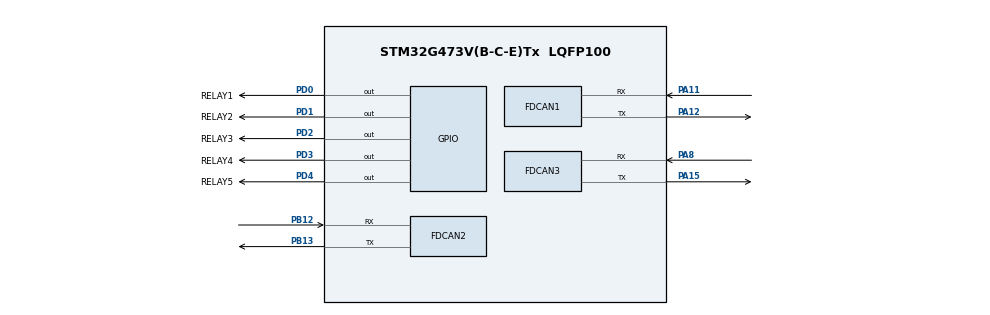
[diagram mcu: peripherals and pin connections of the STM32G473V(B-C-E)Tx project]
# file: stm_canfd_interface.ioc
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FDCAN1.AutoRetransmission=ENABLE
FDCAN1.DataPrescaler=2
FDCAN1.DataSyncJumpWidth=4
FDCAN1.DataTimeSeg1=15
FDCAN1.DataTimeSeg2=4
FDCAN1.FrameFormat=FDCAN_FRAME_FD_BRS
FDCAN1.NominalPrescaler=8
FDCAN1.NominalSyncJumpWidth=4
FDCAN1.NominalTimeSeg1=14
FDCAN1.NominalTimeSeg2=5
FDCAN2.AutoRetransmission=ENABLE
FDCAN2.DataPrescaler=2
FDCAN2.DataSyncJumpWidth=4
FDCAN2.DataTimeSeg1=15
FDCAN2.DataTimeSeg2=4
FDCAN2.FrameFormat=FDCAN_FRAME_FD_BRS
FDCAN2.NominalPrescaler=8
FDCAN2.NominalSyncJumpWidth=4
FDCAN2.NominalTimeSeg1=14
FDCAN2.NominalTimeSeg2=5
FDCAN3.AutoRetransmission=ENABLE
FDCAN3.DataPrescaler=2
FDCAN3.DataSyncJumpWidth=4
FDCAN3.DataTimeSeg1=15
FDCAN3.DataTimeSeg2=4
FDCAN3.FrameFormat=FDCAN_FRAME_FD_BRS
FDCAN3.NominalPrescaler=8
FDCAN3.NominalSyncJumpWidth=4
FDCAN3.NominalTimeSeg1=14
FDCAN3.NominalTimeSeg2=5
FREERTOS.INCLUDE_eTaskGetState=1
FREERTOS.INCLUDE_uxTaskGetStackHighWaterMark=1
FREERTOS.INCLUDE_vTaskDelayUntil=1
FREERTOS.INCLUDE_xTaskGetCurrentTaskHandle=1
FREERTOS.MEMORY_ALLOCATION=2
FREERTOS.Tasks01=defaultTask,0,256,StartDefaultTask,Default,NULL,Dynamic,NULL,NULL
FREERTOS.Timers01=task_5ms,task_5ms_callback,osTimerPeriodic,Default,NULL,Static,task_5msControlBlock;task_10ms,task_10ms_callback,osTimerPeriodic,Default,NULL,Static,task_10msControlBlock;task_100ms,task_100ms_callback,osTimerPeriodic,Default,NULL,Static,task_100msControlBlock
FREERTOS.configCHECK_FOR_STACK_OVERFLOW=1
FREERTOS.configMINIMAL_STACK_SIZE=256
FREERTOS.configRECORD_STACK_HIGH_ADDRESS=1
FREERTOS.configTIMER_TASK_PRIORITY=3
FREERTOS.configTOTAL_HEAP_SIZE=15360
FREERTOS.configUSE_TIMERS=1
Mcu.Family=STM32G4
Mcu.Name=STM32G473V(B-C-E)Tx
Mcu.Package=LQFP100
NVIC.FDCAN1_IT0_IRQn=true\:5\:0\:false\:false\:true\:true\:true\:true\:true
NVIC.FDCAN2_IT0_IRQn=true\:5\:0\:false\:false\:true\:true\:true\:true\:true
NVIC.FDCAN3_IT0_IRQn=true\:5\:0\:false\:false\:true\:true\:true\:true\:true
NVIC.PriorityGroup=NVIC_PRIORITYGROUP_4
NVIC.TIM3_IRQn=true\:5\:0\:false\:false\:true\:true\:true\:true\:true
NVIC.TIM6_DAC_IRQn=true\:5\:0\:false\:false\:true\:true\:true\:true\:true
NVIC.TIM7_DAC_IRQn=true\:0\:0\:false\:false\:true\:false\:false\:true\:true
NVIC.TimeBase=TIM7_DAC_IRQn
NVIC.TimeBaseIP=TIM7
PA11.Mode=FDCAN_Activate
PA11.Signal=FDCAN1_RX
PA12.Mode=FDCAN_Activate
PA12.Signal=FDCAN1_TX
PA13.Mode=Trace_Asynchronous_SW
PA13.Signal=SYS_JTMS-SWDIO
PA14.Mode=Trace_Asynchronous_SW
PA14.Signal=SYS_JTCK-SWCLK
PA15.Mode=FDCAN_Activate
PA15.Signal=FDCAN3_TX
PA8.Mode=FDCAN_Activate
PA8.Signal=FDCAN3_RX
PB12.Mode=FDCAN_Activate
PB12.Signal=FDCAN2_RX
PB13.Mode=FDCAN_Activate
PB13.Signal=FDCAN2_TX
PB3.Mode=Trace_Asynchronous_SW
PB3.Signal=SYS_JTDO-SWO
PD0.GPIO_Label=RELAY1
PD0.Signal=GPIO_Output
PD1.GPIO_Label=RELAY2
PD1.Signal=GPIO_Output
PD2.GPIO_Label=RELAY3
PD2.Signal=GPIO_Output
PD3.GPIO_Label=RELAY4
PD3.Signal=GPIO_Output
PD4.GPIO_Label=RELAY5
PD4.Signal=GPIO_Output
PF0-OSC_IN.Mode=HSE-External-Oscillator
PF0-OSC_IN.Signal=RCC_OSC_IN
PF1-OSC_OUT.Mode=HSE-External-Oscillator
PF1-OSC_OUT.Signal=RCC_OSC_OUT
ProjectManager.HeapSize=0x200
ProjectManager.StackSize=0x400
ProjectManager.TargetToolchain=STM32CubeIDE
RCC.ADC12Freq_Value=80000000
RCC.ADC345Freq_Value=80000000
RCC.AHBFreq_Value=80000000
RCC.APB1Freq_Value=80000000
RCC.APB1TimFreq_Value=80000000
RCC.APB2Freq_Value=80000000
RCC.APB2TimFreq_Value=80000000
RCC.CortexFreq_Value=80000000
RCC.EXTERNAL_CLOCK_VALUE=12288000
RCC.FDCANCLockSelection=RCC_FDCANCLKSOURCE_PLL
RCC.HCLKFreq_Value=80000000
RCC.HSE_VALUE=8000000
RCC.HSI48_VALUE=48000000
RCC.HSI_VALUE=16000000
RCC.LSE_VALUE=32768
RCC.PLLN=20
RCC.PLLSourceVirtual=RCC_PLLSOURCE_HSE
RCC.SYSCLKFreq_VALUE=80000000
RCC.SYSCLKSource=RCC_SYSCLKSOURCE_PLLCLK
RCC.USBFreq_Value=80000000
RCC.VCOOutputFreq_Value=160000000
TIM3.Prescaler=199
TIM3.TIM_MasterOutputTrigger=TIM_TRGO_UPDATE
TIM6.PeriodNoDither=999
TIM6.Prescaler=799
VP_FREERTOS_VS_CMSIS_V1.Mode=CMSIS_V1
VP_SYS_VS_DBSignals.Mode=DisableDeadBatterySignals
VP_SYS_VS_tim7.Mode=TIM7
VP_TIM3_VS_ClockSourceINT.Mode=Internal
VP_TIM6_VS_ClockSourceINT.Mode=Enable_Timer
board=custom

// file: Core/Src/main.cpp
/* USER CODE BEGIN Header */
/**
 ******************************************************************************
 * @file           : main.c
 * @brief          : Main program body
 ******************************************************************************
 * @attention
 *
 * <h2><center>&copy; Copyright (c) 2021 STMicroelectronics.
 * All rights reserved.</center></h2>
 *
 * This software component is licensed by ST under BSD 3-Clause license,
 * the "License"; You may not use this file except in compliance with the
 * License. You may obtain a copy of the License at:
 *                        opensource.org/licenses/BSD-3-Clause
 *
 ******************************************************************************
 */
/* USER CODE END Header */
#include "main.h"
#include "cmsis_os.h"
/* USER CODE BEGIN Includes */
//* bsw
#include "bsw/interface/can_transfer.hpp"
#include "bsw/interface/io_function.hpp"
#include "bsw/interface/adc.hpp"
#include "bsw/interface/dac.hpp"
#include "bsw/buffer.hpp"

//* rte
#include "rte.hpp"
//#include "can_transfer.h"
/* USER CODE END Includes */

ADC_HandleTypeDef hadc1;
DMA_HandleTypeDef hdma_adc1;

DAC_HandleTypeDef hdac1;
DAC_HandleTypeDef hdac2;
DAC_HandleTypeDef hdac3;

OPAMP_HandleTypeDef hopamp1;

FDCAN_HandleTypeDef hfdcan1;
FDCAN_HandleTypeDef hfdcan2;
FDCAN_HandleTypeDef hfdcan3;

TIM_HandleTypeDef htim3;
TIM_HandleTypeDef htim6;

osThreadId defaultTaskHandle;

osTimerId task_10msHandle;
osStaticTimerDef_t task_10msControlBlock;
osTimerId task_20msHandle;
osStaticTimerDef_t task_20msControlBlock;
osTimerId task_40msHandle;
osStaticTimerDef_t task_40msControlBlock;
osTimerId task_50msHandle;
osStaticTimerDef_t task_50msControlBlock;
osTimerId task_100msHandle;
osStaticTimerDef_t task_100msControlBlock;
osTimerId task_200msHandle;
osStaticTimerDef_t task_200msControlBlock;
/* USER CODE BEGIN PV */
// bsw handle
bsw::interface::CanTransfer can_transfer_;
bsw::interface::IoFunction io_function_;
bsw::interface::Buffer user_buffer_;

// rte handler
//* ADC_DAC_ENABLE
bsw::interface::AdcReader adc_reader_;
bsw::interface::DacWriter dac_writer_;
rte::Rte rte_(&can_transfer_, &io_function_);

/* USER CODE END PV */

void SystemClock_Config(void);
static void MX_GPIO_Init(void);

static void MX_FDCAN1_Init(void);
static void MX_FDCAN2_Init(void);
static void MX_FDCAN3_Init(void);

static void MX_TIM3_Init(void);
static void MX_TIM6_Init(void);

static void MX_DMA_Init(void);
static void MX_ADC1_Init(void);
static void MX_ADC1_Init(void);
static void MX_DAC1_Init(void);
static void MX_DAC2_Init(void);
static void MX_DAC3_Init(void);
static void MX_OPAMP1_Init(void);

void StartDefaultTask(void const * argument);
void task_10ms_callback(void const * argument);
void task_20ms_callback(void const * argument);
void task_40ms_callback(void const * argument);
void task_50ms_callback(void const * argument);
void task_100ms_callback(void const * argument);
void task_200ms_callback(void const * argument);

/* USER CODE BEGIN 0 */
#ifdef DEBUG
	static void VectorBase_Config(void)
	{
	  /* The constant array with vectors of the vector table is declared externally in the
	   * c-startup code.
	   */
	  extern const unsigned long g_pfnVectors[];

	  /* Remap the vector table to where the vector table is located for this program. */
	  SCB->VTOR = (unsigned long)&g_pfnVectors[0];
	}

	extern "C" {
		int _write(int file, char *ptr, int len)
		{
			for (int DataIdx = 0; DataIdx < len; DataIdx++)
				ITM_SendChar(*ptr++);

			return len;
		}
	}
#endif

/* USER CODE END 0 */

int main(void)
{
	//* initialize user defined buffer (for A1 interface)
	can_transfer_.initUserBuffer(&user_buffer_);
	can_transfer_.setBus2DeviceBypassMode(false);
	can_transfer_.setMsgFilteringMode(false);

  /* USER CODE BEGIN 1 */
#ifdef DEBUG
  VectorBase_Config();
#endif
  /* USER CODE END 1 */

  /* MCU Configuration--------------------------------------------------------*/

  /* Reset of all peripherals, Initializes the Flash interface and the Systick. */
  HAL_Init();

  /* Configure the system clock */
  SystemClock_Config();

  /* Initialize all configured peripherals */
  MX_GPIO_Init();

  MX_FDCAN1_Init();
  MX_FDCAN2_Init();
  MX_FDCAN3_Init();

  MX_TIM6_Init();
  MX_TIM3_Init();

  //* ADC_DAC_ENABLE
//  MX_DMA_Init();
//  MX_ADC1_Init();
//  MX_DAC1_Init();
//  MX_DAC2_Init();
//  MX_DAC3_Init();
  MX_OPAMP1_Init();

  /* Create the timer(s) */
  /* definition and creation of task_20ms */
  osTimerStaticDef(task_20ms, task_20ms_callback, &task_20msControlBlock);
  task_20msHandle = osTimerCreate(osTimer(task_20ms), osTimerPeriodic, NULL);
  /* definition and creation of task_100ms */
  osTimerStaticDef(task_100ms, task_100ms_callback, &task_100msControlBlock);
  task_100msHandle = osTimerCreate(osTimer(task_100ms), osTimerPeriodic, NULL);
  /* definition and creation of task_200ms */
  osTimerStaticDef(task_200ms, task_200ms_callback, &task_200msControlBlock);
  task_200msHandle = osTimerCreate(osTimer(task_200ms), osTimerPeriodic, NULL);

  /* USER CODE BEGIN RTOS_TIMERS */
  osTimerStart(task_20msHandle, 20);
  osTimerStart(task_100msHandle, 100);
  osTimerStart(task_200msHandle, 200);

  /* start timers, add new ones, ... */
  /* USER CODE END RTOS_TIMERS */

  /* Create the thread(s) */
  /* definition and creation of defaultTask */
  std::string task_name = "defaultTask";
  const osThreadDef_t os_thread_def_defaultTask = {(char*)task_name.c_str(),
												  StartDefaultTask,
												  osPriorityIdle,
												  0,
												  256,
												  NULL,
												  NULL};
  defaultTaskHandle = osThreadCreate(osThread(defaultTask), NULL);

  /* USER CODE BEGIN RTOS_THREADS */
	/* add threads, ... */
  // RTE initialize

  /* USER CODE END RTOS_THREADS */

  /* Start scheduler */
  osKernelStart();

  /* We should never get here as control is now taken by the scheduler */
  /* Infinite loop */
	while (1)
	{

	}
}

void SystemClock_Config(void)
{
  RCC_OscInitTypeDef RCC_OscInitStruct = {0};
  RCC_ClkInitTypeDef RCC_ClkInitStruct = {0};
  RCC_PeriphCLKInitTypeDef PeriphClkInit = {0};

  /** Configure the main internal regulator output voltage
  */
  HAL_PWREx_ControlVoltageScaling(PWR_REGULATOR_VOLTAGE_SCALE1_BOOST);
  /** Initializes the RCC Oscillators according to the specified parameters
  * in the RCC_OscInitTypeDef structure.
  */
  RCC_OscInitStruct.OscillatorType = RCC_OSCILLATORTYPE_HSE;
  RCC_OscInitStruct.HSEState = RCC_HSE_ON;
  RCC_OscInitStruct.PLL.PLLState = RCC_PLL_ON;
  RCC_OscInitStruct.PLL.PLLSource = RCC_PLLSOURCE_HSE;
  RCC_OscInitStruct.PLL.PLLM = RCC_PLLM_DIV1;
  RCC_OscInitStruct.PLL.PLLN = 40;
  RCC_OscInitStruct.PLL.PLLP = RCC_PLLP_DIV2;
  RCC_OscInitStruct.PLL.PLLQ = RCC_PLLQ_DIV4;
  RCC_OscInitStruct.PLL.PLLR = RCC_PLLR_DIV2;
  if (HAL_RCC_OscConfig(&RCC_OscInitStruct) != HAL_OK)
  {
    Error_Handler();
  }
  /** Initializes the CPU, AHB and APB buses clocks
  */
  RCC_ClkInitStruct.ClockType = RCC_CLOCKTYPE_HCLK|RCC_CLOCKTYPE_SYSCLK
                              |RCC_CLOCKTYPE_PCLK1|RCC_CLOCKTYPE_PCLK2;
  RCC_ClkInitStruct.SYSCLKSource = RCC_SYSCLKSOURCE_PLLCLK;
  RCC_ClkInitStruct.AHBCLKDivider = RCC_SYSCLK_DIV1;
  RCC_ClkInitStruct.APB1CLKDivider = RCC_HCLK_DIV1;
  RCC_ClkInitStruct.APB2CLKDivider = RCC_HCLK_DIV1;

  if (HAL_RCC_ClockConfig(&RCC_ClkInitStruct, FLASH_LATENCY_4) != HAL_OK)
  {
    Error_Handler();
  }
  /** Initializes the peripherals clocks
  */
  PeriphClkInit.PeriphClockSelection = RCC_PERIPHCLK_FDCAN;
  PeriphClkInit.FdcanClockSelection = RCC_FDCANCLKSOURCE_PLL;
  if (HAL_RCCEx_PeriphCLKConfig(&PeriphClkInit) != HAL_OK)
  {
    Error_Handler();
  }
}

static void MX_FDCAN1_Init(void)
{

  hfdcan1.Instance = FDCAN1;
  hfdcan1.Init.ClockDivider = FDCAN_CLOCK_DIV1;
  hfdcan1.Init.FrameFormat = FDCAN_FRAME_FD_BRS;
  hfdcan1.Init.Mode = FDCAN_MODE_NORMAL;
  hfdcan1.Init.AutoRetransmission = ENABLE;
  hfdcan1.Init.TransmitPause = DISABLE;
  hfdcan1.Init.ProtocolException = DISABLE;
  hfdcan1.Init.NominalPrescaler = 16;
  hfdcan1.Init.NominalSyncJumpWidth = 2;
  hfdcan1.Init.NominalTimeSeg1 = 7;
  hfdcan1.Init.NominalTimeSeg2 = 2;
  hfdcan1.Init.DataPrescaler = 2;
  hfdcan1.Init.DataSyncJumpWidth = 4;
  hfdcan1.Init.DataTimeSeg1 = 15;
  hfdcan1.Init.DataTimeSeg2 = 4;
  uint8_t buffer_size = can_transfer_.getBufferSize(CAN_CH1);
  hfdcan1.Init.StdFiltersNbr = buffer_size/2 + buffer_size%2;
  hfdcan1.Init.ExtFiltersNbr = 0;
  hfdcan1.Init.TxFifoQueueMode = FDCAN_TX_FIFO_OPERATION;

}

static void MX_FDCAN2_Init(void)
{

  hfdcan2.Instance = FDCAN2;
  hfdcan2.Init.FrameFormat = FDCAN_FRAME_FD_BRS;
  hfdcan2.Init.Mode = FDCAN_MODE_NORMAL;
  hfdcan2.Init.AutoRetransmission = ENABLE;
  hfdcan2.Init.TransmitPause = DISABLE;
  hfdcan2.Init.ProtocolException = DISABLE;
  hfdcan2.Init.NominalPrescaler = 16;
  hfdcan2.Init.NominalSyncJumpWidth = 2;
  hfdcan2.Init.NominalTimeSeg1 = 7;
  hfdcan2.Init.NominalTimeSeg2 = 2;
  hfdcan2.Init.DataPrescaler = 2;
  hfdcan2.Init.DataSyncJumpWidth = 4;
  hfdcan2.Init.DataTimeSeg1 = 15;
  hfdcan2.Init.DataTimeSeg2 = 4;
  uint8_t buffer_size = can_transfer_.getBufferSize(CAN_CH2);
  hfdcan2.Init.StdFiltersNbr = buffer_size/2 + buffer_size%2;
  hfdcan2.Init.ExtFiltersNbr = 0;
  hfdcan2.Init.TxFifoQueueMode = FDCAN_TX_FIFO_OPERATION;

}

static void MX_FDCAN3_Init(void)
{

  hfdcan3.Instance = FDCAN3;
  hfdcan3.Init.FrameFormat = FDCAN_FRAME_FD_BRS;
  hfdcan3.Init.Mode = FDCAN_MODE_NORMAL;
  hfdcan3.Init.AutoRetransmission = ENABLE;
  hfdcan3.Init.TransmitPause = DISABLE;
  hfdcan3.Init.ProtocolException = DISABLE;
  hfdcan3.Init.NominalPrescaler = 16;
  hfdcan3.Init.NominalSyncJumpWidth = 2;
  hfdcan3.Init.NominalTimeSeg1 = 7;
  hfdcan3.Init.NominalTimeSeg2 = 2;
  hfdcan3.Init.DataPrescaler = 2;
  hfdcan3.Init.DataSyncJumpWidth = 4;
  hfdcan3.Init.DataTimeSeg1 = 15;
  hfdcan3.Init.DataTimeSeg2 = 4;
  uint8_t buffer_size = can_transfer_.getBufferSize(CAN_CH3);
  hfdcan3.Init.StdFiltersNbr = buffer_size/2 + buffer_size%2;
  hfdcan3.Init.ExtFiltersNbr = 0;
  hfdcan3.Init.TxFifoQueueMode = FDCAN_TX_FIFO_OPERATION;

}

static void MX_TIM3_Init(void)
{

  TIM_ClockConfigTypeDef sClockSourceConfig = {0};
  TIM_MasterConfigTypeDef sMasterConfig = {0};

  htim3.Instance = TIM3;
  htim3.Init.Prescaler = 199;
  htim3.Init.CounterMode = TIM_COUNTERMODE_UP;
  htim3.Init.Period = 65535;
  htim3.Init.ClockDivision = TIM_CLOCKDIVISION_DIV1;
  htim3.Init.AutoReloadPreload = TIM_AUTORELOAD_PRELOAD_DISABLE;
  if (HAL_TIM_Base_Init(&htim3) != HAL_OK)
  {
    Error_Handler();
  }
  sClockSourceConfig.ClockSource = TIM_CLOCKSOURCE_INTERNAL;
  if (HAL_TIM_ConfigClockSource(&htim3, &sClockSourceConfig) != HAL_OK)
  {
    Error_Handler();
  }
  sMasterConfig.MasterOutputTrigger = TIM_TRGO_UPDATE;
  sMasterConfig.MasterSlaveMode = TIM_MASTERSLAVEMODE_DISABLE;
  if (HAL_TIMEx_MasterConfigSynchronization(&htim3, &sMasterConfig) != HAL_OK)
  {
    Error_Handler();
  }

}

static void MX_TIM6_Init(void)
{

  TIM_MasterConfigTypeDef sMasterConfig = {0};

  htim6.Instance = TIM6;
  htim6.Init.Prescaler = 799;
  htim6.Init.CounterMode = TIM_COUNTERMODE_UP;
  htim6.Init.Period = 999;
  htim6.Init.AutoReloadPreload = TIM_AUTORELOAD_PRELOAD_DISABLE;
  if (HAL_TIM_Base_Init(&htim6) != HAL_OK)
  {
    Error_Handler();
  }
  sMasterConfig.MasterOutputTrigger = TIM_TRGO_RESET;
  sMasterConfig.MasterSlaveMode = TIM_MASTERSLAVEMODE_DISABLE;
  if (HAL_TIMEx_MasterConfigSynchronization(&htim6, &sMasterConfig) != HAL_OK)
  {
    Error_Handler();
  }

}

static void MX_GPIO_Init(void)
{
  GPIO_InitTypeDef GPIO_InitStruct = {0};

  /* GPIO Ports Clock Enable */
  __HAL_RCC_GPIOF_CLK_ENABLE();
  __HAL_RCC_GPIOC_CLK_ENABLE();
  __HAL_RCC_GPIOB_CLK_ENABLE();
  __HAL_RCC_GPIOA_CLK_ENABLE();
  __HAL_RCC_GPIOD_CLK_ENABLE();
  __HAL_RCC_GPIOE_CLK_ENABLE();

  /*Configure GPIO pin Output Level */
  HAL_GPIO_WritePin(GPIOD, RELAY1_Pin|RELAY2_Pin|RELAY3_Pin|RELAY4_Pin
						  |RELAY5_Pin, GPIO_PIN_RESET);
  HAL_GPIO_WritePin(GPIOE, GPIO_PIN_All, GPIO_PIN_RESET);
  HAL_GPIO_WritePin(GPIOC, GPIO_PIN_1, GPIO_PIN_RESET);

  /*Configure GPIO pins : RELAY1_Pin RELAY2_Pin RELAY3_Pin RELAY4_Pin
						   RELAY5_Pin */
  GPIO_InitStruct.Pin = RELAY1_Pin|RELAY2_Pin|RELAY3_Pin|RELAY4_Pin
						  |RELAY5_Pin;
  GPIO_InitStruct.Mode = GPIO_MODE_OUTPUT_PP;
  GPIO_InitStruct.Pull = GPIO_NOPULL;
  GPIO_InitStruct.Speed = GPIO_SPEED_FREQ_LOW;
  HAL_GPIO_Init(GPIOD, &GPIO_InitStruct);

  GPIO_InitStruct.Pin = SSRELAY12_Pin|SSRELAY11_Pin|SSRELAY10_Pin|SSRELAY9_Pin
						  |SSRELAY8_Pin|SSRELAY7_Pin|SSRELAY6_Pin|SSRELAY5_Pin|SSRELAY4_Pin
						  |SSRELAY3_Pin|SSRELAY2_Pin|SSRELAY1_Pin;
  GPIO_InitStruct.Mode = GPIO_MODE_OUTPUT_PP;
  GPIO_InitStruct.Pull = GPIO_NOPULL;
  GPIO_InitStruct.Speed = GPIO_SPEED_FREQ_LOW;
  HAL_GPIO_Init(GPIOE, &GPIO_InitStruct);
}

static void MX_ADC1_Init(void)
{

  ADC_MultiModeTypeDef multimode = {0};
  ADC_ChannelConfTypeDef sConfig = {0};

  /** Common config
  */
  hadc1.Instance = ADC1;
  hadc1.Init.ClockPrescaler = ADC_CLOCK_SYNC_PCLK_DIV4;
  hadc1.Init.Resolution = ADC_RESOLUTION_12B;
  hadc1.Init.DataAlign = ADC_DATAALIGN_RIGHT;
  hadc1.Init.GainCompensation = 0;
  hadc1.Init.ScanConvMode = ADC_SCAN_ENABLE;
  hadc1.Init.EOCSelection = ADC_EOC_SINGLE_CONV;
  hadc1.Init.LowPowerAutoWait = DISABLE;
  hadc1.Init.ContinuousConvMode = ENABLE;
  hadc1.Init.NbrOfConversion = 2;
  hadc1.Init.DiscontinuousConvMode = DISABLE;
  hadc1.Init.ExternalTrigConv = ADC_SOFTWARE_START;
  hadc1.Init.ExternalTrigConvEdge = ADC_EXTERNALTRIGCONVEDGE_NONE;
  hadc1.Init.DMAContinuousRequests = ENABLE;
  hadc1.Init.Overrun = ADC_OVR_DATA_PRESERVED;
  hadc1.Init.OversamplingMode = DISABLE;
  if (HAL_ADC_Init(&hadc1) != HAL_OK)
  {
    Error_Handler();
  }
  /** Configure the ADC multi-mode
  */
  multimode.Mode = ADC_MODE_INDEPENDENT;
  if (HAL_ADCEx_MultiModeConfigChannel(&hadc1, &multimode) != HAL_OK)
  {
    Error_Handler();
  }
  /** Configure Regular Channel
  */
  sConfig.Channel = ADC_CHANNEL_6;
  sConfig.Rank = ADC_REGULAR_RANK_1;
  sConfig.SamplingTime = ADC_SAMPLETIME_247CYCLES_5;
  sConfig.SingleDiff = ADC_SINGLE_ENDED;
  sConfig.OffsetNumber = ADC_OFFSET_NONE;
  sConfig.Offset = 0;
  if (HAL_ADC_ConfigChannel(&hadc1, &sConfig) != HAL_OK)
  {
    Error_Handler();
  }
  /** Configure Regular Channel
  */
  sConfig.Channel = ADC_CHANNEL_8;
  sConfig.Rank = ADC_REGULAR_RANK_2;
  if (HAL_ADC_ConfigChannel(&hadc1, &sConfig) != HAL_OK)
  {
    Error_Handler();
  }

}

static void MX_DAC1_Init(void)
{

  DAC_ChannelConfTypeDef sConfig = {0};

  /** DAC Initialization
  */
  hdac1.Instance = DAC1;
  if (HAL_DAC_Init(&hdac1) != HAL_OK)
  {
    Error_Handler();
  }
  /** DAC channel OUT1 config
  */
  sConfig.DAC_HighFrequency = DAC_HIGH_FREQUENCY_INTERFACE_MODE_AUTOMATIC;
  sConfig.DAC_DMADoubleDataMode = DISABLE;
  sConfig.DAC_SignedFormat = DISABLE;
  sConfig.DAC_SampleAndHold = DAC_SAMPLEANDHOLD_DISABLE;
  sConfig.DAC_Trigger = DAC_TRIGGER_NONE;
  sConfig.DAC_Trigger2 = DAC_TRIGGER_NONE;
  sConfig.DAC_OutputBuffer = DAC_OUTPUTBUFFER_ENABLE;
  sConfig.DAC_ConnectOnChipPeripheral = DAC_CHIPCONNECT_EXTERNAL;
  sConfig.DAC_UserTrimming = DAC_TRIMMING_FACTORY;
  if (HAL_DAC_ConfigChannel(&hdac1, &sConfig, DAC_CHANNEL_1) != HAL_OK)
  {
    Error_Handler();
  }
  /** DAC channel OUT2 config
  */
  if (HAL_DAC_ConfigChannel(&hdac1, &sConfig, DAC_CHANNEL_2) != HAL_OK)
  {
    Error_Handler();
  }

}

static void MX_DAC2_Init(void)
{

  DAC_ChannelConfTypeDef sConfig = {0};

  /** DAC Initialization
  */
  hdac2.Instance = DAC2;
  if (HAL_DAC_Init(&hdac2) != HAL_OK)
  {
    Error_Handler();
  }
  /** DAC channel OUT1 config
  */
  sConfig.DAC_HighFrequency = DAC_HIGH_FREQUENCY_INTERFACE_MODE_AUTOMATIC;
  sConfig.DAC_DMADoubleDataMode = DISABLE;
  sConfig.DAC_SignedFormat = DISABLE;
  sConfig.DAC_SampleAndHold = DAC_SAMPLEANDHOLD_DISABLE;
  sConfig.DAC_Trigger = DAC_TRIGGER_NONE;
  sConfig.DAC_Trigger2 = DAC_TRIGGER_NONE;
  sConfig.DAC_OutputBuffer = DAC_OUTPUTBUFFER_ENABLE;
  sConfig.DAC_ConnectOnChipPeripheral = DAC_CHIPCONNECT_EXTERNAL;
  sConfig.DAC_UserTrimming = DAC_TRIMMING_FACTORY;
  if (HAL_DAC_ConfigChannel(&hdac2, &sConfig, DAC_CHANNEL_1) != HAL_OK)
  {
    Error_Handler();
  }

}

static void MX_DAC3_Init(void)
{

  DAC_ChannelConfTypeDef sConfig = {0};

  /** DAC Initialization
  */
  hdac3.Instance = DAC3;
  if (HAL_DAC_Init(&hdac3) != HAL_OK)
  {
    Error_Handler();
  }
  /** DAC channel OUT1 config
  */
  sConfig.DAC_HighFrequency = DAC_HIGH_FREQUENCY_INTERFACE_MODE_AUTOMATIC;
  sConfig.DAC_DMADoubleDataMode = DISABLE;
  sConfig.DAC_SignedFormat = DISABLE;
  sConfig.DAC_SampleAndHold = DAC_SAMPLEANDHOLD_DISABLE;
  sConfig.DAC_Trigger = DAC_TRIGGER_NONE;
  sConfig.DAC_Trigger2 = DAC_TRIGGER_NONE;
  sConfig.DAC_OutputBuffer = DAC_OUTPUTBUFFER_DISABLE;
  sConfig.DAC_ConnectOnChipPeripheral = DAC_CHIPCONNECT_INTERNAL;
  sConfig.DAC_UserTrimming = DAC_TRIMMING_FACTORY;
  if (HAL_DAC_ConfigChannel(&hdac3, &sConfig, DAC_CHANNEL_1) != HAL_OK)
  {
    Error_Handler();
  }

}

static void MX_OPAMP1_Init(void)
{

  hopamp1.Instance = OPAMP1;
  hopamp1.Init.PowerMode = OPAMP_POWERMODE_NORMALSPEED;
  hopamp1.Init.Mode = OPAMP_FOLLOWER_MODE;
  hopamp1.Init.NonInvertingInput = OPAMP_NONINVERTINGINPUT_DAC;
  hopamp1.Init.InternalOutput = DISABLE;
  hopamp1.Init.TimerControlledMuxmode = OPAMP_TIMERCONTROLLEDMUXMODE_DISABLE;
  hopamp1.Init.UserTrimming = OPAMP_TRIMMING_FACTORY;
  if (HAL_OPAMP_Init(&hopamp1) != HAL_OK)
  {
    Error_Handler();
  }

}

static void MX_DMA_Init(void)
{

  /* DMA controller clock enable */
  __HAL_RCC_DMAMUX1_CLK_ENABLE();
  __HAL_RCC_DMA1_CLK_ENABLE();

  /* DMA interrupt init */
  /* DMA1_Channel1_IRQn interrupt configuration */
  HAL_NVIC_SetPriority(DMA1_Channel1_IRQn, 5, 0);
  HAL_NVIC_EnableIRQ(DMA1_Channel1_IRQn);

}

void StartDefaultTask(void const * argument)
{
  /* USER CODE BEGIN 5 */
	can_transfer_.init(&hfdcan1, &hfdcan2, &hfdcan3);

	dac_writer_.initDac(&hdac1);
	dac_writer_.initDac(&hdac2);
	dac_writer_.initDac(&hdac3);

	rte_.initRte();

	/* Infinite loop */
	for(;;)
	{
		osDelay(500);
	}

  /* USER CODE END 5 */
}

/* task_20ms_callback function */
void task_20ms_callback(void const * argument)
{
  /* USER CODE BEGIN task_20ms_callback */
	if(rte_.isInit()){
		rte_.task20ms();
	}
  /* USER CODE END task_20ms_callback */
}

/* task_100ms_callback function */
void task_100ms_callback(void const * argument)
{
  /* USER CODE BEGIN task_100ms_callback */
	if(rte_.isInit()){
		rte_.task100ms();
	}
  /* USER CODE END task_100ms_callback */
}

/* task_200ms_callback function */
void task_200ms_callback(void const * argument)
{
  /* USER CODE BEGIN task_200ms_callback */
	if(rte_.isInit()){
		rte_.task200ms();
	}
  /* USER CODE END task_200ms_callback */
}

 /**
  * @brief  Period elapsed callback in non blocking mode
  * @note   This function is called  when TIM7 interrupt took place, inside
  * HAL_TIM_IRQHandler(). It makes a direct call to HAL_IncTick() to increment
  * a global variable "uwTick" used as application time base.
  * @param  htim : TIM handle
  * @retval None
  */
void HAL_TIM_PeriodElapsedCallback(TIM_HandleTypeDef *htim)
{
  if (htim->Instance == TIM7) {
    HAL_IncTick();
  }
  /* USER CODE BEGIN Callback 1 */
	if(htim->Instance == TIM6)
	{
	}

  /* USER CODE END Callback 1 */
}

void Error_Handler(void)
{
	__disable_irq();
	while (1)
	{
	}
}

/************************ (C) COPYRIGHT STMicroelectronics *****END OF FILE****/
